VERSION 5.7 ;
  NOWIREEXTENSIONATPIN ON ;
  DIVIDERCHAR "/" ;
  BUSBITCHARS "[]" ;
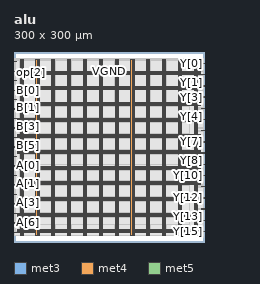
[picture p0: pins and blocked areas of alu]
MACRO alu
  CLASS BLOCK ;
  FOREIGN alu ;
  ORIGIN 0.000 0.000 ;
  SIZE 300.000 BY 300.000 ;
  PIN A[0]
    DIRECTION INPUT ;
    USE SIGNAL ;
    ANTENNAGATEAREA 0.742500 ;
    PORT
      LAYER met3 ;
        RECT 0.000 119.720 4.000 120.320 ;
    END
  END A[0]
  PIN A[1]
    DIRECTION INPUT ;
    USE SIGNAL ;
    ANTENNAGATEAREA 0.852000 ;
    PORT
      LAYER met3 ;
        RECT 0.000 104.760 4.000 105.360 ;
    END
  END A[1]
  PIN A[2]
    DIRECTION INPUT ;
    USE SIGNAL ;
    ANTENNAGATEAREA 0.426000 ;
    PORT
      LAYER met3 ;
        RECT 0.000 89.800 4.000 90.400 ;
    END
  END A[2]
  PIN A[3]
    DIRECTION INPUT ;
    USE SIGNAL ;
    ANTENNAGATEAREA 0.852000 ;
    PORT
      LAYER met3 ;
        RECT 0.000 74.840 4.000 75.440 ;
    END
  END A[3]
  PIN A[4]
    DIRECTION INPUT ;
    USE SIGNAL ;
    ANTENNAGATEAREA 0.213000 ;
    PORT
      LAYER met3 ;
        RECT 0.000 59.880 4.000 60.480 ;
    END
  END A[4]
  PIN A[5]
    DIRECTION INPUT ;
    USE SIGNAL ;
    ANTENNAGATEAREA 0.742500 ;
    PORT
      LAYER met3 ;
        RECT 0.000 44.920 4.000 45.520 ;
    END
  END A[5]
  PIN A[6]
    DIRECTION INPUT ;
    USE SIGNAL ;
    ANTENNAGATEAREA 0.742500 ;
    PORT
      LAYER met3 ;
        RECT 0.000 29.960 4.000 30.560 ;
    END
  END A[6]
  PIN A[7]
    DIRECTION INPUT ;
    USE SIGNAL ;
    ANTENNAGATEAREA 0.495000 ;
    PORT
      LAYER met3 ;
        RECT 0.000 15.000 4.000 15.600 ;
    END
  END A[7]
  PIN B[0]
    DIRECTION INPUT ;
    USE SIGNAL ;
    ANTENNAGATEAREA 0.495000 ;
    PORT
      LAYER met3 ;
        RECT 0.000 239.400 4.000 240.000 ;
    END
  END B[0]
  PIN B[1]
    DIRECTION INPUT ;
    USE SIGNAL ;
    ANTENNAGATEAREA 0.990000 ;
    PORT
      LAYER met3 ;
        RECT 0.000 224.440 4.000 225.040 ;
    END
  END B[1]
  PIN B[2]
    DIRECTION INPUT ;
    USE SIGNAL ;
    ANTENNAGATEAREA 0.495000 ;
    PORT
      LAYER met3 ;
        RECT 0.000 209.480 4.000 210.080 ;
    END
  END B[2]
  PIN B[3]
    DIRECTION INPUT ;
    USE SIGNAL ;
    ANTENNAGATEAREA 0.742500 ;
    PORT
      LAYER met3 ;
        RECT 0.000 194.520 4.000 195.120 ;
    END
  END B[3]
  PIN B[4]
    DIRECTION INPUT ;
    USE SIGNAL ;
    ANTENNAGATEAREA 0.495000 ;
    PORT
      LAYER met3 ;
        RECT 0.000 179.560 4.000 180.160 ;
    END
  END B[4]
  PIN B[5]
    DIRECTION INPUT ;
    USE SIGNAL ;
    ANTENNAGATEAREA 0.213000 ;
    PORT
      LAYER met3 ;
        RECT 0.000 164.600 4.000 165.200 ;
    END
  END B[5]
  PIN B[6]
    DIRECTION INPUT ;
    USE SIGNAL ;
    ANTENNAGATEAREA 0.213000 ;
    PORT
      LAYER met3 ;
        RECT 0.000 149.640 4.000 150.240 ;
    END
  END B[6]
  PIN B[7]
    DIRECTION INPUT ;
    USE SIGNAL ;
    ANTENNAGATEAREA 0.852000 ;
    PORT
      LAYER met3 ;
        RECT 0.000 134.680 4.000 135.280 ;
    END
  END B[7]
  PIN VGND
    DIRECTION INOUT ;
    USE GROUND ;
    PORT
      LAYER met4 ;
        RECT 13.020 10.640 14.620 288.560 ;
    END
    PORT
      LAYER met4 ;
        RECT 38.020 10.640 39.620 288.560 ;
    END
    PORT
      LAYER met4 ;
        RECT 63.020 10.640 64.620 288.560 ;
    END
    PORT
      LAYER met4 ;
        RECT 88.020 10.640 89.620 288.560 ;
    END
    PORT
      LAYER met4 ;
        RECT 113.020 10.640 114.620 288.560 ;
    END
    PORT
      LAYER met4 ;
        RECT 138.020 10.640 139.620 288.560 ;
    END
    PORT
      LAYER met4 ;
        RECT 163.020 10.640 164.620 288.560 ;
    END
    PORT
      LAYER met4 ;
        RECT 188.020 10.640 189.620 288.560 ;
    END
    PORT
      LAYER met4 ;
        RECT 213.020 10.640 214.620 288.560 ;
    END
    PORT
      LAYER met4 ;
        RECT 238.020 10.640 239.620 288.560 ;
    END
    PORT
      LAYER met4 ;
        RECT 263.020 10.640 264.620 288.560 ;
    END
    PORT
      LAYER met4 ;
        RECT 288.020 10.640 289.620 288.560 ;
    END
    PORT
      LAYER met5 ;
        RECT 5.280 18.380 294.640 19.980 ;
    END
    PORT
      LAYER met5 ;
        RECT 5.280 43.380 294.640 44.980 ;
    END
    PORT
      LAYER met5 ;
        RECT 5.280 68.380 294.640 69.980 ;
    END
    PORT
      LAYER met5 ;
        RECT 5.280 93.380 294.640 94.980 ;
    END
    PORT
      LAYER met5 ;
        RECT 5.280 118.380 294.640 119.980 ;
    END
    PORT
      LAYER met5 ;
        RECT 5.280 143.380 294.640 144.980 ;
    END
    PORT
      LAYER met5 ;
        RECT 5.280 168.380 294.640 169.980 ;
    END
    PORT
      LAYER met5 ;
        RECT 5.280 193.380 294.640 194.980 ;
    END
    PORT
      LAYER met5 ;
        RECT 5.280 218.380 294.640 219.980 ;
    END
    PORT
      LAYER met5 ;
        RECT 5.280 243.380 294.640 244.980 ;
    END
    PORT
      LAYER met5 ;
        RECT 5.280 268.380 294.640 269.980 ;
    END
  END VGND
  PIN VPWR
    DIRECTION INOUT ;
    USE POWER ;
    PORT
      LAYER met4 ;
        RECT 9.720 10.640 11.320 288.560 ;
    END
    PORT
      LAYER met4 ;
        RECT 34.720 10.640 36.320 288.560 ;
    END
    PORT
      LAYER met4 ;
        RECT 59.720 10.640 61.320 288.560 ;
    END
    PORT
      LAYER met4 ;
        RECT 84.720 10.640 86.320 288.560 ;
    END
    PORT
      LAYER met4 ;
        RECT 109.720 10.640 111.320 288.560 ;
    END
    PORT
      LAYER met4 ;
        RECT 134.720 10.640 136.320 288.560 ;
    END
    PORT
      LAYER met4 ;
        RECT 159.720 10.640 161.320 288.560 ;
    END
    PORT
      LAYER met4 ;
        RECT 184.720 10.640 186.320 288.560 ;
    END
    PORT
      LAYER met4 ;
        RECT 209.720 10.640 211.320 288.560 ;
    END
    PORT
      LAYER met4 ;
        RECT 234.720 10.640 236.320 288.560 ;
    END
    PORT
      LAYER met4 ;
        RECT 259.720 10.640 261.320 288.560 ;
    END
    PORT
      LAYER met4 ;
        RECT 284.720 10.640 286.320 288.560 ;
    END
    PORT
      LAYER met5 ;
        RECT 5.280 15.080 294.640 16.680 ;
    END
    PORT
      LAYER met5 ;
        RECT 5.280 40.080 294.640 41.680 ;
    END
    PORT
      LAYER met5 ;
        RECT 5.280 65.080 294.640 66.680 ;
    END
    PORT
      LAYER met5 ;
        RECT 5.280 90.080 294.640 91.680 ;
    END
    PORT
      LAYER met5 ;
        RECT 5.280 115.080 294.640 116.680 ;
    END
    PORT
      LAYER met5 ;
        RECT 5.280 140.080 294.640 141.680 ;
    END
    PORT
      LAYER met5 ;
        RECT 5.280 165.080 294.640 166.680 ;
    END
    PORT
      LAYER met5 ;
        RECT 5.280 190.080 294.640 191.680 ;
    END
    PORT
      LAYER met5 ;
        RECT 5.280 215.080 294.640 216.680 ;
    END
    PORT
      LAYER met5 ;
        RECT 5.280 240.080 294.640 241.680 ;
    END
    PORT
      LAYER met5 ;
        RECT 5.280 265.080 294.640 266.680 ;
    END
  END VPWR
  PIN Y[0]
    DIRECTION OUTPUT TRISTATE ;
    USE SIGNAL ;
    ANTENNADIFFAREA 0.445500 ;
    PORT
      LAYER met3 ;
        RECT 296.000 281.560 300.000 282.160 ;
    END
  END Y[0]
  PIN Y[10]
    DIRECTION OUTPUT TRISTATE ;
    USE SIGNAL ;
    ANTENNADIFFAREA 0.445500 ;
    PORT
      LAYER met3 ;
        RECT 296.000 104.760 300.000 105.360 ;
    END
  END Y[10]
  PIN Y[11]
    DIRECTION OUTPUT TRISTATE ;
    USE SIGNAL ;
    ANTENNADIFFAREA 0.445500 ;
    PORT
      LAYER met3 ;
        RECT 296.000 87.080 300.000 87.680 ;
    END
  END Y[11]
  PIN Y[12]
    DIRECTION OUTPUT TRISTATE ;
    USE SIGNAL ;
    ANTENNADIFFAREA 0.445500 ;
    PORT
      LAYER met3 ;
        RECT 296.000 69.400 300.000 70.000 ;
    END
  END Y[12]
  PIN Y[13]
    DIRECTION OUTPUT TRISTATE ;
    USE SIGNAL ;
    ANTENNADIFFAREA 0.445500 ;
    PORT
      LAYER met3 ;
        RECT 296.000 51.720 300.000 52.320 ;
    END
  END Y[13]
  PIN Y[14]
    DIRECTION OUTPUT TRISTATE ;
    USE SIGNAL ;
    ANTENNADIFFAREA 0.795200 ;
    PORT
      LAYER met3 ;
        RECT 296.000 34.040 300.000 34.640 ;
    END
  END Y[14]
  PIN Y[15]
    DIRECTION OUTPUT TRISTATE ;
    USE SIGNAL ;
    ANTENNADIFFAREA 0.445500 ;
    PORT
      LAYER met3 ;
        RECT 296.000 16.360 300.000 16.960 ;
    END
  END Y[15]
  PIN Y[1]
    DIRECTION OUTPUT TRISTATE ;
    USE SIGNAL ;
    ANTENNADIFFAREA 0.445500 ;
    PORT
      LAYER met3 ;
        RECT 296.000 263.880 300.000 264.480 ;
    END
  END Y[1]
  PIN Y[2]
    DIRECTION OUTPUT TRISTATE ;
    USE SIGNAL ;
    ANTENNADIFFAREA 0.795200 ;
    PORT
      LAYER met3 ;
        RECT 296.000 246.200 300.000 246.800 ;
    END
  END Y[2]
  PIN Y[3]
    DIRECTION OUTPUT TRISTATE ;
    USE SIGNAL ;
    ANTENNADIFFAREA 0.445500 ;
    PORT
      LAYER met3 ;
        RECT 296.000 228.520 300.000 229.120 ;
    END
  END Y[3]
  PIN Y[4]
    DIRECTION OUTPUT TRISTATE ;
    USE SIGNAL ;
    ANTENNADIFFAREA 0.445500 ;
    PORT
      LAYER met3 ;
        RECT 296.000 210.840 300.000 211.440 ;
    END
  END Y[4]
  PIN Y[5]
    DIRECTION OUTPUT TRISTATE ;
    USE SIGNAL ;
    ANTENNADIFFAREA 0.445500 ;
    PORT
      LAYER met3 ;
        RECT 296.000 193.160 300.000 193.760 ;
    END
  END Y[5]
  PIN Y[6]
    DIRECTION OUTPUT TRISTATE ;
    USE SIGNAL ;
    ANTENNADIFFAREA 0.445500 ;
    PORT
      LAYER met3 ;
        RECT 296.000 175.480 300.000 176.080 ;
    END
  END Y[6]
  PIN Y[7]
    DIRECTION OUTPUT TRISTATE ;
    USE SIGNAL ;
    ANTENNADIFFAREA 0.795200 ;
    PORT
      LAYER met3 ;
        RECT 296.000 157.800 300.000 158.400 ;
    END
  END Y[7]
  PIN Y[8]
    DIRECTION OUTPUT TRISTATE ;
    USE SIGNAL ;
    ANTENNADIFFAREA 0.445500 ;
    PORT
      LAYER met3 ;
        RECT 296.000 140.120 300.000 140.720 ;
    END
  END Y[8]
  PIN Y[9]
    DIRECTION OUTPUT TRISTATE ;
    USE SIGNAL ;
    ANTENNADIFFAREA 0.445500 ;
    PORT
      LAYER met3 ;
        RECT 296.000 122.440 300.000 123.040 ;
    END
  END Y[9]
  PIN op[0]
    DIRECTION INPUT ;
    USE SIGNAL ;
    ANTENNAGATEAREA 0.213000 ;
    PORT
      LAYER met3 ;
        RECT 0.000 284.280 4.000 284.880 ;
    END
  END op[0]
  PIN op[1]
    DIRECTION INPUT ;
    USE SIGNAL ;
    ANTENNAGATEAREA 0.426000 ;
    PORT
      LAYER met3 ;
        RECT 0.000 269.320 4.000 269.920 ;
    END
  END op[1]
  PIN op[2]
    DIRECTION INPUT ;
    USE SIGNAL ;
    ANTENNAGATEAREA 0.247500 ;
    PORT
      LAYER met3 ;
        RECT 0.000 254.360 4.000 254.960 ;
    END
  END op[2]
  OBS
      LAYER li1 ;
        RECT 5.520 10.795 294.400 288.405 ;
      LAYER met1 ;
        RECT 0.530 9.900 299.850 289.300 ;
      LAYER met2 ;
        RECT 0.560 9.870 299.820 289.330 ;
      LAYER met3 ;
        RECT 1.445 285.280 298.475 288.485 ;
        RECT 4.400 283.880 298.475 285.280 ;
        RECT 1.445 282.560 298.475 283.880 ;
        RECT 1.445 281.160 295.600 282.560 ;
        RECT 1.445 270.320 298.475 281.160 ;
        RECT 4.400 268.920 298.475 270.320 ;
        RECT 1.445 264.880 298.475 268.920 ;
        RECT 1.445 263.480 295.600 264.880 ;
        RECT 1.445 255.360 298.475 263.480 ;
        RECT 4.400 253.960 298.475 255.360 ;
        RECT 1.445 247.200 298.475 253.960 ;
        RECT 1.445 245.800 295.600 247.200 ;
        RECT 1.445 240.400 298.475 245.800 ;
        RECT 4.400 239.000 298.475 240.400 ;
        RECT 1.445 229.520 298.475 239.000 ;
        RECT 1.445 228.120 295.600 229.520 ;
        RECT 1.445 225.440 298.475 228.120 ;
        RECT 4.400 224.040 298.475 225.440 ;
        RECT 1.445 211.840 298.475 224.040 ;
        RECT 1.445 210.480 295.600 211.840 ;
        RECT 4.400 210.440 295.600 210.480 ;
        RECT 4.400 209.080 298.475 210.440 ;
        RECT 1.445 195.520 298.475 209.080 ;
        RECT 4.400 194.160 298.475 195.520 ;
        RECT 4.400 194.120 295.600 194.160 ;
        RECT 1.445 192.760 295.600 194.120 ;
        RECT 1.445 180.560 298.475 192.760 ;
        RECT 4.400 179.160 298.475 180.560 ;
        RECT 1.445 176.480 298.475 179.160 ;
        RECT 1.445 175.080 295.600 176.480 ;
        RECT 1.445 165.600 298.475 175.080 ;
        RECT 4.400 164.200 298.475 165.600 ;
        RECT 1.445 158.800 298.475 164.200 ;
        RECT 1.445 157.400 295.600 158.800 ;
        RECT 1.445 150.640 298.475 157.400 ;
        RECT 4.400 149.240 298.475 150.640 ;
        RECT 1.445 141.120 298.475 149.240 ;
        RECT 1.445 139.720 295.600 141.120 ;
        RECT 1.445 135.680 298.475 139.720 ;
        RECT 4.400 134.280 298.475 135.680 ;
        RECT 1.445 123.440 298.475 134.280 ;
        RECT 1.445 122.040 295.600 123.440 ;
        RECT 1.445 120.720 298.475 122.040 ;
        RECT 4.400 119.320 298.475 120.720 ;
        RECT 1.445 105.760 298.475 119.320 ;
        RECT 4.400 104.360 295.600 105.760 ;
        RECT 1.445 90.800 298.475 104.360 ;
        RECT 4.400 89.400 298.475 90.800 ;
        RECT 1.445 88.080 298.475 89.400 ;
        RECT 1.445 86.680 295.600 88.080 ;
        RECT 1.445 75.840 298.475 86.680 ;
        RECT 4.400 74.440 298.475 75.840 ;
        RECT 1.445 70.400 298.475 74.440 ;
        RECT 1.445 69.000 295.600 70.400 ;
        RECT 1.445 60.880 298.475 69.000 ;
        RECT 4.400 59.480 298.475 60.880 ;
        RECT 1.445 52.720 298.475 59.480 ;
        RECT 1.445 51.320 295.600 52.720 ;
        RECT 1.445 45.920 298.475 51.320 ;
        RECT 4.400 44.520 298.475 45.920 ;
        RECT 1.445 35.040 298.475 44.520 ;
        RECT 1.445 33.640 295.600 35.040 ;
        RECT 1.445 30.960 298.475 33.640 ;
        RECT 4.400 29.560 298.475 30.960 ;
        RECT 1.445 17.360 298.475 29.560 ;
        RECT 1.445 16.000 295.600 17.360 ;
        RECT 4.400 15.960 295.600 16.000 ;
        RECT 4.400 14.600 298.475 15.960 ;
        RECT 1.445 10.715 298.475 14.600 ;
      LAYER met4 ;
        RECT 3.055 16.495 9.320 286.785 ;
        RECT 11.720 16.495 12.620 286.785 ;
        RECT 15.020 16.495 34.320 286.785 ;
        RECT 36.720 16.495 37.620 286.785 ;
        RECT 40.020 16.495 59.320 286.785 ;
        RECT 61.720 16.495 62.620 286.785 ;
        RECT 65.020 16.495 84.320 286.785 ;
        RECT 86.720 16.495 87.620 286.785 ;
        RECT 90.020 16.495 109.320 286.785 ;
        RECT 111.720 16.495 112.620 286.785 ;
        RECT 115.020 16.495 134.320 286.785 ;
        RECT 136.720 16.495 137.620 286.785 ;
        RECT 140.020 16.495 159.320 286.785 ;
        RECT 161.720 16.495 162.620 286.785 ;
        RECT 165.020 16.495 184.320 286.785 ;
        RECT 186.720 16.495 187.620 286.785 ;
        RECT 190.020 16.495 209.320 286.785 ;
        RECT 211.720 16.495 212.620 286.785 ;
        RECT 215.020 16.495 234.320 286.785 ;
        RECT 236.720 16.495 237.620 286.785 ;
        RECT 240.020 16.495 259.320 286.785 ;
        RECT 261.720 16.495 262.620 286.785 ;
        RECT 265.020 16.495 284.320 286.785 ;
        RECT 286.720 16.495 287.620 286.785 ;
      LAYER met5 ;
        RECT 7.940 196.580 277.260 213.300 ;
        RECT 7.940 171.580 277.260 188.480 ;
        RECT 7.940 146.580 277.260 163.480 ;
        RECT 7.940 121.580 277.260 138.480 ;
        RECT 7.940 96.580 277.260 113.480 ;
        RECT 7.940 71.580 277.260 88.480 ;
        RECT 7.940 46.580 277.260 63.480 ;
        RECT 7.940 28.100 277.260 38.480 ;
  END
END alu
END LIBRARY

